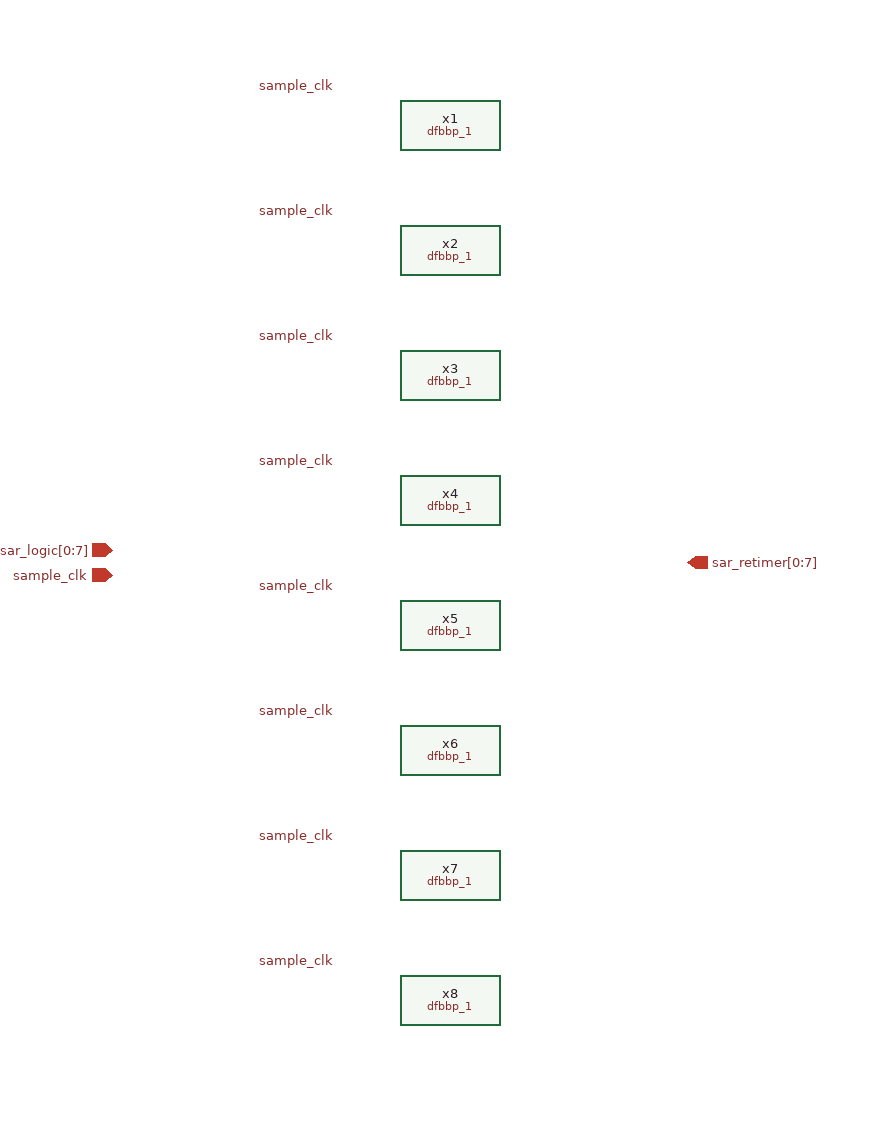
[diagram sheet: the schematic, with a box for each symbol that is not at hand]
v {xschem version=3.4.0 file_version=1.2
}
G {}
K {}
V {}
S {}
E {}
C {sky130_stdcells/dfbbp_1.sym} 740 -960 0 0 {name=x1 VGND=VGND VNB=VNB VPB=VPB VPWR=VPWR prefix=sky130_fd_sc_hd__ }
C {sky130_stdcells/dfbbp_1.sym} 740 -860 0 0 {name=x2 VGND=VGND VNB=VNB VPB=VPB VPWR=VPWR prefix=sky130_fd_sc_hd__ }
C {sky130_stdcells/dfbbp_1.sym} 740 -760 0 0 {name=x3 VGND=VGND VNB=VNB VPB=VPB VPWR=VPWR prefix=sky130_fd_sc_hd__ }
C {sky130_stdcells/dfbbp_1.sym} 740 -660 0 0 {name=x4 VGND=VGND VNB=VNB VPB=VPB VPWR=VPWR prefix=sky130_fd_sc_hd__ }
C {sky130_stdcells/dfbbp_1.sym} 740 -560 0 0 {name=x5 VGND=VGND VNB=VNB VPB=VPB VPWR=VPWR prefix=sky130_fd_sc_hd__ }
C {sky130_stdcells/dfbbp_1.sym} 740 -460 0 0 {name=x6 VGND=VGND VNB=VNB VPB=VPB VPWR=VPWR prefix=sky130_fd_sc_hd__ }
C {sky130_stdcells/dfbbp_1.sym} 740 -360 0 0 {name=x7 VGND=VGND VNB=VNB VPB=VPB VPWR=VPWR prefix=sky130_fd_sc_hd__ }
C {sky130_stdcells/dfbbp_1.sym} 740 -260 0 0 {name=x8 VGND=VGND VNB=VNB VPB=VPB VPWR=VPWR prefix=sky130_fd_sc_hd__ }
C {devices/ipin.sym} 470 -620 0 0 {name=p31 lab=sar_logic[0:7]}
C {devices/opin.sym} 930 -610 0 0 {name=p57 lab=sar_retimer[0:7]}
C {devices/noconn.sym} 830 -270 0 1 {name=l1}
C {devices/noconn.sym} 830 -370 0 1 {name=l2}
C {devices/noconn.sym} 830 -470 0 1 {name=l3}
C {devices/noconn.sym} 830 -570 0 1 {name=l4}
C {devices/noconn.sym} 830 -670 0 1 {name=l5}
C {devices/noconn.sym} 830 -770 0 1 {name=l6}
C {devices/noconn.sym} 830 -870 0 1 {name=l7}
C {devices/noconn.sym} 830 -970 0 1 {name=l8}
C {devices/noconn.sym} 650 -950 0 0 {name=l9}
C {devices/noconn.sym} 650 -930 0 0 {name=l10}
C {devices/noconn.sym} 650 -850 0 0 {name=l11}
C {devices/noconn.sym} 650 -830 0 0 {name=l12}
C {devices/noconn.sym} 650 -750 0 0 {name=l13}
C {devices/noconn.sym} 650 -730 0 0 {name=l14}
C {devices/noconn.sym} 650 -650 0 0 {name=l15}
C {devices/noconn.sym} 650 -630 0 0 {name=l16}
C {devices/noconn.sym} 650 -550 0 0 {name=l17}
C {devices/noconn.sym} 650 -530 0 0 {name=l18}
C {devices/noconn.sym} 650 -450 0 0 {name=l19}
C {devices/noconn.sym} 650 -430 0 0 {name=l20}
C {devices/noconn.sym} 650 -350 0 0 {name=l21}
C {devices/noconn.sym} 650 -330 0 0 {name=l22}
C {devices/noconn.sym} 650 -250 0 0 {name=l23}
C {devices/noconn.sym} 650 -230 0 0 {name=l24}
C {devices/ipin.sym} 470 -600 0 0 {name=p1 lab=sample_clk}
C {devices/lab_pin.sym} 650 -990 2 1 {name=p33 sig_type=std_logic lab=sample_clk}
C {devices/lab_pin.sym} 650 -890 2 1 {name=p2 sig_type=std_logic lab=sample_clk}
C {devices/lab_pin.sym} 650 -790 2 1 {name=p3 sig_type=std_logic lab=sample_clk}
C {devices/lab_pin.sym} 650 -690 2 1 {name=p4 sig_type=std_logic lab=sample_clk}
C {devices/lab_pin.sym} 650 -590 2 1 {name=p5 sig_type=std_logic lab=sample_clk}
C {devices/lab_pin.sym} 650 -490 2 1 {name=p6 sig_type=std_logic lab=sample_clk}
C {devices/lab_pin.sym} 650 -390 2 1 {name=p7 sig_type=std_logic lab=sample_clk}
C {devices/lab_pin.sym} 650 -290 2 1 {name=p8 sig_type=std_logic lab=sample_clk}
